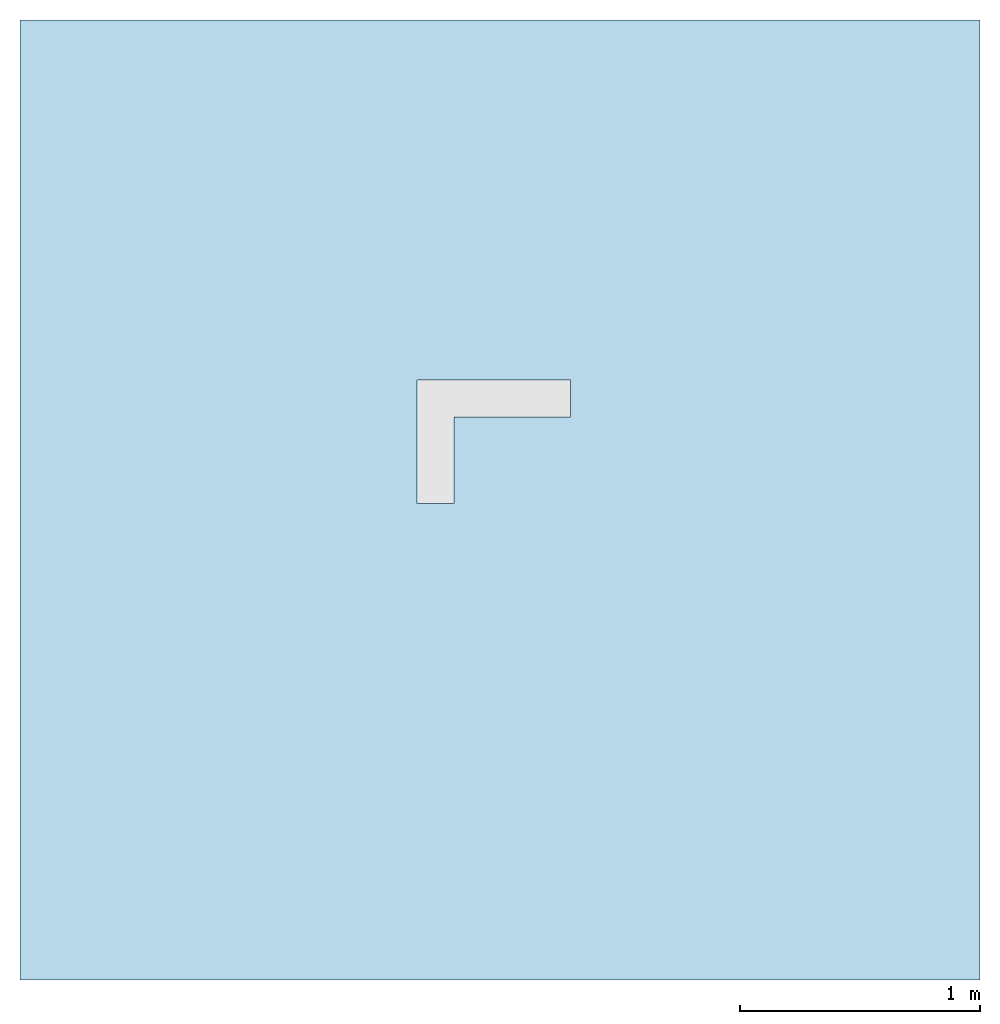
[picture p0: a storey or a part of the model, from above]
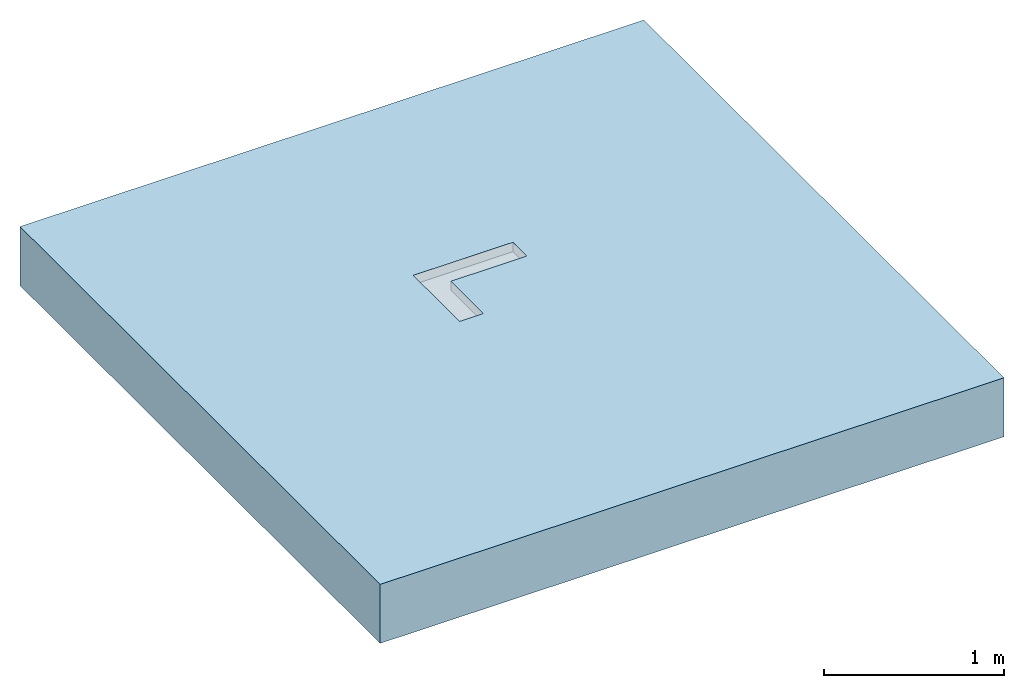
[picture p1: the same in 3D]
Properties of the parts of a building model (IFC2X3)

# File
Description: ViewDefinition [CoordinationView]
File name: 105207 - Corner Unit Channel - Right Hand - 500mm LG - Invert Depth 50mm.ifc
Time: 2014-03-20T10:10:27
Written by: Autodesk Revit 2013
Made in: 20120221_2030(x64)

# IfcProject, Project Number
LongName: Project Name; Phase: Project Status

# IfcSite, Default
RefLatitude: 42, 21, 30, 344238; RefLongitude: -71, -3, -35, -194702; RefElevation: 0 mm

# IfcBuilding
Pset_BuildingCommon - NumberOfStoreys: 1
Other - Project Address: ## Street City, State Zip; Project Name: Project Name; Project Status: Project Status; Client Name: Owner; Project Issue Date: Issue Date; Project Number: Project Number

# IfcBuildingStorey, Level 1
LongName: Level 1; Elevation: 0 mm
Constraints - Elevation Base: 0; Elevation: 0 mm
Graphics - Line Pattern: Center; Symbol at End 1 Default: no; Line Weight: 1; Symbol: M_Level Head - Circle: M_Level Head - Circle; Symbol at End 2 Default: yes; Color: 0
Identity Data - Structural: no; Name: Level 1; Building Story: yes
Dimensions - Computation Height: 0 mm

# IfcFlowTerminal: 105207 - Corner Unit Channel - Right Hand - 500mm LG - Invert Depth 50mm, ACO BD Modular 125 Corner Units:105207 - Corner Unit Channel - Right Hand - 500mm LG - Invert Depth 50mm:105207 - Corner Unit Channel - Right Hand - 500mm LG - Invert Depth 50mm:213559
In: Level 1
Material: Stainless Steel AISI 304 (F), Polystyrene, High Impact (F)
Phasing - Phase Created: New Construction
Construction - 105521 - Slotted Locked - Stainless Steel 304 - 500mm long: no; 96819 - Grating - Heal Safe - Stainless Steel 304 - 500mm long: no; 105537 - Intercept Locked - Stainless Steel 304 - 500mm long: no; 49061 & 49062_Vinyl Seal: no; 21920 - Grating - Plain Mesh - Stainless Steel 304 - 500mm long: no; 105846 - Slip Resistant Intercept - Stainless Steel 304 - 500mm long: no; 21720 - Grating - Plain Mesh - Stainless Steel 304 - 500mm long: no; 105528 - Quadrato Locked - Stainless Steel 304 - 500mm long: no; 105530 - Quadrato - Stainless Steel 304 - 500mm long: no; 402072- Grating - Heal Safe Locked - Stainless Steel 304 - 500mm long: no; End Plate Invert Right: no; 21910 - Grating - Slip Resistant Mesh - Stainless Steel 304 - 500mm long: no; 26270_PVC Infill: yes; End Plate Invert Left: no; 21740 - - Ladder - Stainless Steel 304 - 500mm long: no; End Plate Invert: no; 105844 - Slip Resistant Quadrato Locked - Stainless Steel 304 - 500mm long: no; 105842 - Slip Resistant Quadrato - Stainless Steel 304 - 500mm long: no; 105505 - Perforated Locked - Stainless Steel 304 - 500mm long: no; 15704 - Composite - Black Composite - 500mm long: no; 21710 - Grating - Slip Resistant Mesh - Stainless Steel 304 - 500mm long: no; 10735 - Composite - White Composite - 500mm long: no; 105848 - Slip Resistant Intercept Locked - Stainless Steel 304 - 500mm long: no; 105539 - Intercept - Stainless Steel 304 - 500mm long: no; 21790 - Plastic - White Plastic - 500mm long: no; 105519 - Slotted Locked - Stainless Steel 304 - 500mm long: no; Grating (Left): no; Grating (Right): yes; Detail 80mm: no; Right Hand Corner Unit: yes; Grating: yes; Connecting Plate (Left): no; Detail 65mm: no; Left Hand Corner Unit: no; Detail 125mm: no; Detail 50mm: yes; Detail 95mm: no; Detail 110mm: no; Connecting Plate (Right): yes
Other - Neoprene Gasket: 1; Rigid PVC Extrusion (49061): 0 mm; PVC Infill (26270): 2000 mm; Flexible PVC Seal (49062): 0 mm; Detail H: 61.3 mm
Constraints - Level: Level: Level 1; Moves With Nearby Elements: no
Identity Data - Mark: 2; Watermarked By: www.acobd.com; Watermark2: This file is water marked and users are prohibited to reproduce, adapt, distribute this information; Manufacturer: ACO Building Drainage; Website: www.acobd.com; Address: ACO Business Centre, Caxton Road, Bedford, MK41 0LF; Fax: +44 (0)1462 851490; E-mail Technical: abdtechnical@aco.co.uk; Watermarked With: BIM Manager Premium Suite; E-mail Sales: abdcommercial@aco.co.uk; Telephone: +44 (0)1462 816666; Watermark1: This file is the property of ACO Technologies PLC
Model Properties - Grating Product Code 105848: Load Class A15 - Slip Resistant Intercept Locked - Stainless Steel 304 - 500mm long - 1.8kg; Grating Product Code 21920: Load Class C250 - Plain Mesh - Stainless Steel 304 - 500mm long - 2.2kg; Grating Product Code 105528: Load Class A15 - Quadrato Locked - Stainless Steel 304 - 500mm long - 1.6kg; Grating Product Code 105846: Load Class A15 - Slip Resistant Intercept - Stainless Steel 304 - 500mm long - 1.8kg; Grating Product Code 105530: Load Class A15 - Quadrato - Stainless Steel 304 - 500mm long - 1.6kg; Grating Product Code 105844: Load Class A15 - Slip Resistant Quadrato Locked - Stainless Steel 304 - 500mm long - 1.6kg; Grating Product Code 105842: Load Class A15 - Slip Resistant Quadrato - Stainless Steel 304 - 500mm long - 1.6kg; Grating Product Code 21790: Load Class A15 - Plastic - White Plastic - 500mm long - 0.6kg; Grating Product Code 21910: Load Class C250 - Slip Resistant Mesh - Stainless Steel 304 - 500mm long - 2.2kg; Grating Product Code 105521: Load Class C250 - Slotted Locked - Stainless Steel 304 - 500mm long - 2.3kg; Grating Product Code 15704: Load Class C250 - Composite - Black Composite - 500mm long - 1.2kg; Grating Product Code 105539: Load Class A15 - Intercept - Stainless Steel 304 - 500mm long - 1.8kg; Grating Product Code 105519: Load Class A15 - Slotted Locked - Stainless Steel 304 - 500mm long - 1.0kg; End Plate Product Code 105105: N/A; Grating Product Code 105505: Load Class C250 - Perforated Locked - Stainless Steel 304 - 500mm long - 1.8kg; End Plate Product Code 105104: N/A; End Plate Product Code 105103: N/A; Grating Product Code 96819: Load Class B125 - Heal Safe - Stainless Steel 304 - 500mm long - 2.0kg; End Plate Product Code 105101: N/A; End Plate Product Code 105102: N/A; Grating Product Code 10735: Load Class C250 - Composite - White Composite - 500mm long - 1.2kg; Grating Product Code 105537: Load Class A15 - Intercept Locked - Stainless Steel 304 - 500mm long - 1.8kg; Grating Product Code 21710: Load Class A15 - Slip Resistant Mesh - Stainless Steel 304 - 500mm long - 1.6kg; Grating Product Code 21740: Load Class C250 - Ladder - Stainless Steel 304 - 500mm long - 2.0kg; Grating Product Code 402072: Load Class B125 - Heal Safe Locked - Stainless Steel 304 - 500mm long - 2.0kg; Grating Product Code 21720: Load Class A15 - Plain Mesh - Stainless Steel 304 - 500mm long - 1.6kg; End Plate Product Code 105100: End Plate Stainless Steel 304 for Invert Depth - 50mm - 0.2Kg
General - Channel Recycled Material Content: 60-70%; Channel Material: Stainless Steel Grade 304; Seal Colour: Black; Load Class: A15 - C250; Channel Recyclable: Fully recyclable; Channel Colour: Mid Grey; Price: POA - contact ACO; Installation guidelines: X:\Electronic Literature\ABD Electronic Literature\Standard Stainless Steel and Galvanised Steel Channels\ACO Modular 125\ACO Modular 125.pdf; Dimensions (LxWxH): 500 x 514 x 50; Product Code: 105207; Seal Recycled Material Content: 0%; Seal Material: Neoprene; Maintenance guidelines: X:\Electronic Literature\ABD Electronic Literature\Standard Stainless Steel and Galvanised Steel Channels\ACO Modular 125\ACO Modular 125.pdf; Product Type: Stainless Steel Channel Drainage System; NBS Specification: NBS Section Q10 Kerbs/edgings/channels/paving accessories, Clause 180 Drainage Channel Systems; Product Range: ACO Modular 125; Weight (Kg): 3.9; Product Description: ACO Modular 125 500mm Corner Unit Right Hand; Seal Recyclable: Fully recyclable; Product Standard: BS EN 1433:2002, CE marked
Dimensions - Grating Height: 21 mm; Angle: 90 deg; Depth: 29 mm; Invert Depth: 50 mm; Endplate V Length: 1139 mm; Floor Void Depth: 62.8 mm

# IfcOpeningElement: Recess
In: Level 1
Dimensions - Volume: 6390391600 mm3; Area: 16000000 mm2; Thickness: 400 mm; Perimeter: 16000 mm
Phasing - Phase Created: New Construction
Structural - Structural: no; Enable Analytical Model: no
Constraints - Room Bounding: yes; Level: Level: Level 1; Related to Mass: no; Height Offset From Level: 0 mm
Analytical Properties - Absorptance: 0.1; Roughness: 1; Thermal Resistance (R): 0.382409; Thermal mass: 604440; Heat Transfer Coefficient (U): 2.615
Construction - Default Thickness: 400 mm; Function: 0
Graphics - Coarse Scale Fill Color: 0
Materials and Finishes - Structural Material: Concrete, Broom Finish

# IfcSlab: Floor:Generic Floor - 400mm, Floor:Generic Floor - 400mm:193825
In: Level 1
PredefinedType: FLOOR; Material: Concrete, Broom Finish 400 mm
Dimensions - Volume: 6390391600 mm3; Area: 16000000 mm2; Thickness: 400 mm; Perimeter: 16000 mm
Phasing - Phase Created: New Construction
Structural - Structural: no; Enable Analytical Model: no
Constraints - Room Bounding: yes; Level: Level: Level 1; Related to Mass: no; Height Offset From Level: 0 mm
Pset_SlabCommon - Reference: Generic Floor - 400mm; IsExternal: no; LoadBearing: yes
Analytical Properties - Absorptance: 0.1; Roughness: 1; Thermal Resistance (R): 0.382409; Thermal mass: 604440; Heat Transfer Coefficient (U): 2.615
Construction - Default Thickness: 400 mm; Function: 0
Graphics - Coarse Scale Fill Color: 0
Materials and Finishes - Structural Material: Concrete, Broom Finish
